# Generated deterministically by seda-macro-lef-normalizer-v1; recipe orfs-ng45-fakeram-metal3-coupledl2-pg-v1.
VERSION 5.8 ;
BUSBITCHARS "[]" ;
DIVIDERCHAR "/" ;

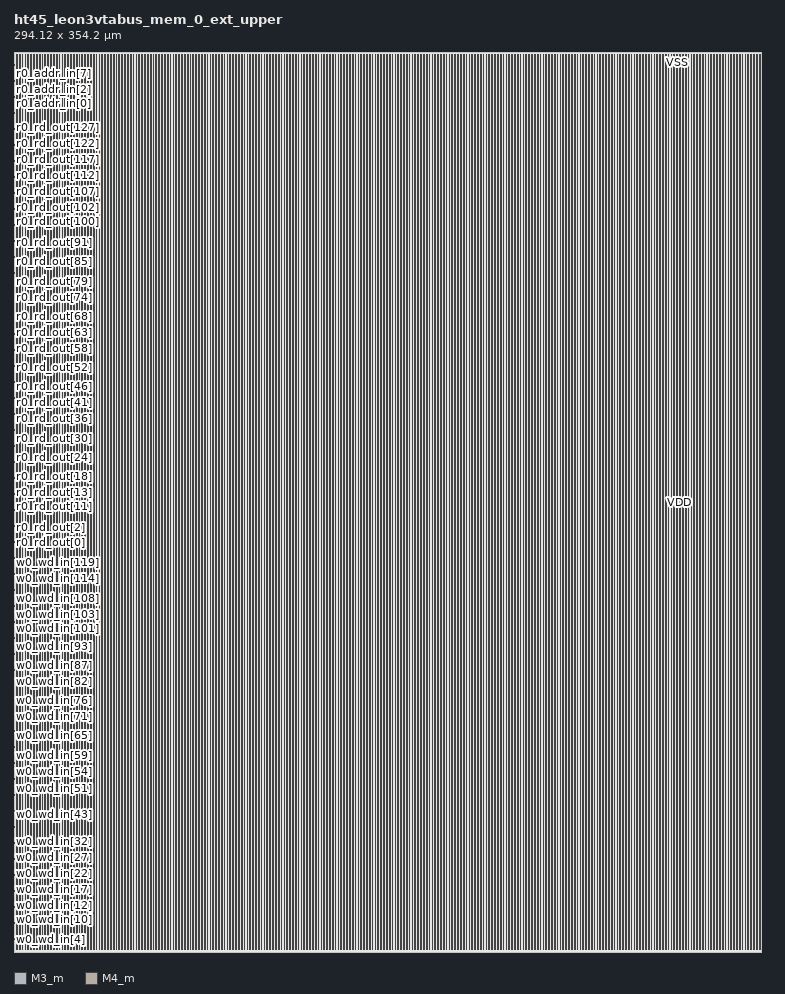
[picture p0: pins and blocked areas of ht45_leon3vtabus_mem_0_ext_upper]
MACRO ht45_leon3vtabus_mem_0_ext_upper
  FOREIGN ht45_leon3vtabus_mem_0_ext_upper 0 0 ;
  CLASS COVER ;
  ORIGIN 0 0 ;
  SIZE 294.12 BY 354.2 ;
  SYMMETRY X Y R90 ;
  PIN w0_wd_in[0]
    DIRECTION INPUT ;
    USE SIGNAL ;
    SHAPE ABUTMENT ;
    PORT
      LAYER M3_m ;
      RECT 0 0.035 0.07 0.105 ;
    END
  END w0_wd_in[0]
  PIN w0_wd_in[1]
    DIRECTION INPUT ;
    USE SIGNAL ;
    SHAPE ABUTMENT ;
    PORT
      LAYER M3_m ;
      RECT 0 1.295 0.07 1.365 ;
    END
  END w0_wd_in[1]
  PIN w0_wd_in[2]
    DIRECTION INPUT ;
    USE SIGNAL ;
    SHAPE ABUTMENT ;
    PORT
      LAYER M3_m ;
      RECT 0 2.555 0.07 2.625 ;
    END
  END w0_wd_in[2]
  PIN w0_wd_in[3]
    DIRECTION INPUT ;
    USE SIGNAL ;
    SHAPE ABUTMENT ;
    PORT
      LAYER M3_m ;
      RECT 0 3.815 0.07 3.885 ;
    END
  END w0_wd_in[3]
  PIN w0_wd_in[4]
    DIRECTION INPUT ;
    USE SIGNAL ;
    SHAPE ABUTMENT ;
    PORT
      LAYER M3_m ;
      RECT 0 5.075 0.07 5.145 ;
    END
  END w0_wd_in[4]
  PIN w0_wd_in[5]
    DIRECTION INPUT ;
    USE SIGNAL ;
    SHAPE ABUTMENT ;
    PORT
      LAYER M3_m ;
      RECT 0 6.335 0.07 6.405 ;
    END
  END w0_wd_in[5]
  PIN w0_wd_in[6]
    DIRECTION INPUT ;
    USE SIGNAL ;
    SHAPE ABUTMENT ;
    PORT
      LAYER M3_m ;
      RECT 0 7.595 0.07 7.665 ;
    END
  END w0_wd_in[6]
  PIN w0_wd_in[7]
    DIRECTION INPUT ;
    USE SIGNAL ;
    SHAPE ABUTMENT ;
    PORT
      LAYER M3_m ;
      RECT 0 8.855 0.07 8.925 ;
    END
  END w0_wd_in[7]
  PIN w0_wd_in[8]
    DIRECTION INPUT ;
    USE SIGNAL ;
    SHAPE ABUTMENT ;
    PORT
      LAYER M3_m ;
      RECT 0 10.115 0.07 10.185 ;
    END
  END w0_wd_in[8]
  PIN w0_wd_in[9]
    DIRECTION INPUT ;
    USE SIGNAL ;
    SHAPE ABUTMENT ;
    PORT
      LAYER M3_m ;
      RECT 0 11.375 0.07 11.445 ;
    END
  END w0_wd_in[9]
  PIN w0_wd_in[10]
    DIRECTION INPUT ;
    USE SIGNAL ;
    SHAPE ABUTMENT ;
    PORT
      LAYER M3_m ;
      RECT 0 12.635 0.07 12.705 ;
    END
  END w0_wd_in[10]
  PIN w0_wd_in[11]
    DIRECTION INPUT ;
    USE SIGNAL ;
    SHAPE ABUTMENT ;
    PORT
      LAYER M3_m ;
      RECT 0 13.895 0.07 13.965 ;
    END
  END w0_wd_in[11]
  PIN w0_wd_in[12]
    DIRECTION INPUT ;
    USE SIGNAL ;
    SHAPE ABUTMENT ;
    PORT
      LAYER M3_m ;
      RECT 0 15.155 0.07 15.225 ;
    END
  END w0_wd_in[12]
  PIN w0_wd_in[13]
    DIRECTION INPUT ;
    USE SIGNAL ;
    SHAPE ABUTMENT ;
    PORT
      LAYER M3_m ;
      RECT 0 16.415 0.07 16.485 ;
    END
  END w0_wd_in[13]
  PIN w0_wd_in[14]
    DIRECTION INPUT ;
    USE SIGNAL ;
    SHAPE ABUTMENT ;
    PORT
      LAYER M3_m ;
      RECT 0 17.675 0.07 17.745 ;
    END
  END w0_wd_in[14]
  PIN w0_wd_in[15]
    DIRECTION INPUT ;
    USE SIGNAL ;
    SHAPE ABUTMENT ;
    PORT
      LAYER M3_m ;
      RECT 0 18.935 0.07 19.005 ;
    END
  END w0_wd_in[15]
  PIN w0_wd_in[16]
    DIRECTION INPUT ;
    USE SIGNAL ;
    SHAPE ABUTMENT ;
    PORT
      LAYER M3_m ;
      RECT 0 20.195 0.07 20.265 ;
    END
  END w0_wd_in[16]
  PIN w0_wd_in[17]
    DIRECTION INPUT ;
    USE SIGNAL ;
    SHAPE ABUTMENT ;
    PORT
      LAYER M3_m ;
      RECT 0 21.455 0.07 21.525 ;
    END
  END w0_wd_in[17]
  PIN w0_wd_in[18]
    DIRECTION INPUT ;
    USE SIGNAL ;
    SHAPE ABUTMENT ;
    PORT
      LAYER M3_m ;
      RECT 0 22.715 0.07 22.785 ;
    END
  END w0_wd_in[18]
  PIN w0_wd_in[19]
    DIRECTION INPUT ;
    USE SIGNAL ;
    SHAPE ABUTMENT ;
    PORT
      LAYER M3_m ;
      RECT 0 23.975 0.07 24.045 ;
    END
  END w0_wd_in[19]
  PIN w0_wd_in[20]
    DIRECTION INPUT ;
    USE SIGNAL ;
    SHAPE ABUTMENT ;
    PORT
      LAYER M3_m ;
      RECT 0 25.235 0.07 25.305 ;
    END
  END w0_wd_in[20]
  PIN w0_wd_in[21]
    DIRECTION INPUT ;
    USE SIGNAL ;
    SHAPE ABUTMENT ;
    PORT
      LAYER M3_m ;
      RECT 0 26.495 0.07 26.565 ;
    END
  END w0_wd_in[21]
  PIN w0_wd_in[22]
    DIRECTION INPUT ;
    USE SIGNAL ;
    SHAPE ABUTMENT ;
    PORT
      LAYER M3_m ;
      RECT 0 27.755 0.07 27.825 ;
    END
  END w0_wd_in[22]
  PIN w0_wd_in[23]
    DIRECTION INPUT ;
    USE SIGNAL ;
    SHAPE ABUTMENT ;
    PORT
      LAYER M3_m ;
      RECT 0 29.015 0.07 29.085 ;
    END
  END w0_wd_in[23]
  PIN w0_wd_in[24]
    DIRECTION INPUT ;
    USE SIGNAL ;
    SHAPE ABUTMENT ;
    PORT
      LAYER M3_m ;
      RECT 0 30.275 0.07 30.345 ;
    END
  END w0_wd_in[24]
  PIN w0_wd_in[25]
    DIRECTION INPUT ;
    USE SIGNAL ;
    SHAPE ABUTMENT ;
    PORT
      LAYER M3_m ;
      RECT 0 31.535 0.07 31.605 ;
    END
  END w0_wd_in[25]
  PIN w0_wd_in[26]
    DIRECTION INPUT ;
    USE SIGNAL ;
    SHAPE ABUTMENT ;
    PORT
      LAYER M3_m ;
      RECT 0 32.795 0.07 32.865 ;
    END
  END w0_wd_in[26]
  PIN w0_wd_in[27]
    DIRECTION INPUT ;
    USE SIGNAL ;
    SHAPE ABUTMENT ;
    PORT
      LAYER M3_m ;
      RECT 0 34.055 0.07 34.125 ;
    END
  END w0_wd_in[27]
  PIN w0_wd_in[28]
    DIRECTION INPUT ;
    USE SIGNAL ;
    SHAPE ABUTMENT ;
    PORT
      LAYER M3_m ;
      RECT 0 35.315 0.07 35.385 ;
    END
  END w0_wd_in[28]
  PIN w0_wd_in[29]
    DIRECTION INPUT ;
    USE SIGNAL ;
    SHAPE ABUTMENT ;
    PORT
      LAYER M3_m ;
      RECT 0 36.575 0.07 36.645 ;
    END
  END w0_wd_in[29]
  PIN w0_wd_in[30]
    DIRECTION INPUT ;
    USE SIGNAL ;
    SHAPE ABUTMENT ;
    PORT
      LAYER M3_m ;
      RECT 0 37.835 0.07 37.905 ;
    END
  END w0_wd_in[30]
  PIN w0_wd_in[31]
    DIRECTION INPUT ;
    USE SIGNAL ;
    SHAPE ABUTMENT ;
    PORT
      LAYER M3_m ;
      RECT 0 39.095 0.07 39.165 ;
    END
  END w0_wd_in[31]
  PIN w0_wd_in[32]
    DIRECTION INPUT ;
    USE SIGNAL ;
    SHAPE ABUTMENT ;
    PORT
      LAYER M3_m ;
      RECT 0 40.355 0.07 40.425 ;
    END
  END w0_wd_in[32]
  PIN w0_wd_in[33]
    DIRECTION INPUT ;
    USE SIGNAL ;
    SHAPE ABUTMENT ;
    PORT
      LAYER M3_m ;
      RECT 0 41.615 0.07 41.685 ;
    END
  END w0_wd_in[33]
  PIN w0_wd_in[34]
    DIRECTION INPUT ;
    USE SIGNAL ;
    SHAPE ABUTMENT ;
    PORT
      LAYER M3_m ;
      RECT 0 42.875 0.07 42.945 ;
    END
  END w0_wd_in[34]
  PIN w0_wd_in[35]
    DIRECTION INPUT ;
    USE SIGNAL ;
    SHAPE ABUTMENT ;
    PORT
      LAYER M3_m ;
      RECT 0 44.135 0.07 44.205 ;
    END
  END w0_wd_in[35]
  PIN w0_wd_in[36]
    DIRECTION INPUT ;
    USE SIGNAL ;
    SHAPE ABUTMENT ;
    PORT
      LAYER M3_m ;
      RECT 0 45.395 0.07 45.465 ;
    END
  END w0_wd_in[36]
  PIN w0_wd_in[37]
    DIRECTION INPUT ;
    USE SIGNAL ;
    SHAPE ABUTMENT ;
    PORT
      LAYER M3_m ;
      RECT 0 46.655 0.07 46.725 ;
    END
  END w0_wd_in[37]
  PIN w0_wd_in[38]
    DIRECTION INPUT ;
    USE SIGNAL ;
    SHAPE ABUTMENT ;
    PORT
      LAYER M3_m ;
      RECT 0 47.915 0.07 47.985 ;
    END
  END w0_wd_in[38]
  PIN w0_wd_in[39]
    DIRECTION INPUT ;
    USE SIGNAL ;
    SHAPE ABUTMENT ;
    PORT
      LAYER M3_m ;
      RECT 0 49.175 0.07 49.245 ;
    END
  END w0_wd_in[39]
  PIN w0_wd_in[40]
    DIRECTION INPUT ;
    USE SIGNAL ;
    SHAPE ABUTMENT ;
    PORT
      LAYER M3_m ;
      RECT 0 50.435 0.07 50.505 ;
    END
  END w0_wd_in[40]
  PIN w0_wd_in[41]
    DIRECTION INPUT ;
    USE SIGNAL ;
    SHAPE ABUTMENT ;
    PORT
      LAYER M3_m ;
      RECT 0 51.695 0.07 51.765 ;
    END
  END w0_wd_in[41]
  PIN w0_wd_in[42]
    DIRECTION INPUT ;
    USE SIGNAL ;
    SHAPE ABUTMENT ;
    PORT
      LAYER M3_m ;
      RECT 0 52.955 0.07 53.025 ;
    END
  END w0_wd_in[42]
  PIN w0_wd_in[43]
    DIRECTION INPUT ;
    USE SIGNAL ;
    SHAPE ABUTMENT ;
    PORT
      LAYER M3_m ;
      RECT 0 54.215 0.07 54.285 ;
    END
  END w0_wd_in[43]
  PIN w0_wd_in[44]
    DIRECTION INPUT ;
    USE SIGNAL ;
    SHAPE ABUTMENT ;
    PORT
      LAYER M3_m ;
      RECT 0 55.475 0.07 55.545 ;
    END
  END w0_wd_in[44]
  PIN w0_wd_in[45]
    DIRECTION INPUT ;
    USE SIGNAL ;
    SHAPE ABUTMENT ;
    PORT
      LAYER M3_m ;
      RECT 0 56.735 0.07 56.805 ;
    END
  END w0_wd_in[45]
  PIN w0_wd_in[46]
    DIRECTION INPUT ;
    USE SIGNAL ;
    SHAPE ABUTMENT ;
    PORT
      LAYER M3_m ;
      RECT 0 57.995 0.07 58.065 ;
    END
  END w0_wd_in[46]
  PIN w0_wd_in[47]
    DIRECTION INPUT ;
    USE SIGNAL ;
    SHAPE ABUTMENT ;
    PORT
      LAYER M3_m ;
      RECT 0 59.255 0.07 59.325 ;
    END
  END w0_wd_in[47]
  PIN w0_wd_in[48]
    DIRECTION INPUT ;
    USE SIGNAL ;
    SHAPE ABUTMENT ;
    PORT
      LAYER M3_m ;
      RECT 0 60.515 0.07 60.585 ;
    END
  END w0_wd_in[48]
  PIN w0_wd_in[49]
    DIRECTION INPUT ;
    USE SIGNAL ;
    SHAPE ABUTMENT ;
    PORT
      LAYER M3_m ;
      RECT 0 61.775 0.07 61.845 ;
    END
  END w0_wd_in[49]
  PIN w0_wd_in[50]
    DIRECTION INPUT ;
    USE SIGNAL ;
    SHAPE ABUTMENT ;
    PORT
      LAYER M3_m ;
      RECT 0 63.035 0.07 63.105 ;
    END
  END w0_wd_in[50]
  PIN w0_wd_in[51]
    DIRECTION INPUT ;
    USE SIGNAL ;
    SHAPE ABUTMENT ;
    PORT
      LAYER M3_m ;
      RECT 0 64.295 0.07 64.365 ;
    END
  END w0_wd_in[51]
  PIN w0_wd_in[52]
    DIRECTION INPUT ;
    USE SIGNAL ;
    SHAPE ABUTMENT ;
    PORT
      LAYER M3_m ;
      RECT 0 65.555 0.07 65.625 ;
    END
  END w0_wd_in[52]
  PIN w0_wd_in[53]
    DIRECTION INPUT ;
    USE SIGNAL ;
    SHAPE ABUTMENT ;
    PORT
      LAYER M3_m ;
      RECT 0 66.815 0.07 66.885 ;
    END
  END w0_wd_in[53]
  PIN w0_wd_in[54]
    DIRECTION INPUT ;
    USE SIGNAL ;
    SHAPE ABUTMENT ;
    PORT
      LAYER M3_m ;
      RECT 0 68.075 0.07 68.145 ;
    END
  END w0_wd_in[54]
  PIN w0_wd_in[55]
    DIRECTION INPUT ;
    USE SIGNAL ;
    SHAPE ABUTMENT ;
    PORT
      LAYER M3_m ;
      RECT 0 69.335 0.07 69.405 ;
    END
  END w0_wd_in[55]
  PIN w0_wd_in[56]
    DIRECTION INPUT ;
    USE SIGNAL ;
    SHAPE ABUTMENT ;
    PORT
      LAYER M3_m ;
      RECT 0 70.595 0.07 70.665 ;
    END
  END w0_wd_in[56]
  PIN w0_wd_in[57]
    DIRECTION INPUT ;
    USE SIGNAL ;
    SHAPE ABUTMENT ;
    PORT
      LAYER M3_m ;
      RECT 0 71.855 0.07 71.925 ;
    END
  END w0_wd_in[57]
  PIN w0_wd_in[58]
    DIRECTION INPUT ;
    USE SIGNAL ;
    SHAPE ABUTMENT ;
    PORT
      LAYER M3_m ;
      RECT 0 73.115 0.07 73.185 ;
    END
  END w0_wd_in[58]
  PIN w0_wd_in[59]
    DIRECTION INPUT ;
    USE SIGNAL ;
    SHAPE ABUTMENT ;
    PORT
      LAYER M3_m ;
      RECT 0 74.375 0.07 74.445 ;
    END
  END w0_wd_in[59]
  PIN w0_wd_in[60]
    DIRECTION INPUT ;
    USE SIGNAL ;
    SHAPE ABUTMENT ;
    PORT
      LAYER M3_m ;
      RECT 0 75.635 0.07 75.705 ;
    END
  END w0_wd_in[60]
  PIN w0_wd_in[61]
    DIRECTION INPUT ;
    USE SIGNAL ;
    SHAPE ABUTMENT ;
    PORT
      LAYER M3_m ;
      RECT 0 76.895 0.07 76.965 ;
    END
  END w0_wd_in[61]
  PIN w0_wd_in[62]
    DIRECTION INPUT ;
    USE SIGNAL ;
    SHAPE ABUTMENT ;
    PORT
      LAYER M3_m ;
      RECT 0 78.155 0.07 78.225 ;
    END
  END w0_wd_in[62]
  PIN w0_wd_in[63]
    DIRECTION INPUT ;
    USE SIGNAL ;
    SHAPE ABUTMENT ;
    PORT
      LAYER M3_m ;
      RECT 0 79.415 0.07 79.485 ;
    END
  END w0_wd_in[63]
  PIN w0_wd_in[64]
    DIRECTION INPUT ;
    USE SIGNAL ;
    SHAPE ABUTMENT ;
    PORT
      LAYER M3_m ;
      RECT 0 80.675 0.07 80.745 ;
    END
  END w0_wd_in[64]
  PIN w0_wd_in[65]
    DIRECTION INPUT ;
    USE SIGNAL ;
    SHAPE ABUTMENT ;
    PORT
      LAYER M3_m ;
      RECT 0 81.935 0.07 82.005 ;
    END
  END w0_wd_in[65]
  PIN w0_wd_in[66]
    DIRECTION INPUT ;
    USE SIGNAL ;
    SHAPE ABUTMENT ;
    PORT
      LAYER M3_m ;
      RECT 0 83.195 0.07 83.265 ;
    END
  END w0_wd_in[66]
  PIN w0_wd_in[67]
    DIRECTION INPUT ;
    USE SIGNAL ;
    SHAPE ABUTMENT ;
    PORT
      LAYER M3_m ;
      RECT 0 84.455 0.07 84.525 ;
    END
  END w0_wd_in[67]
  PIN w0_wd_in[68]
    DIRECTION INPUT ;
    USE SIGNAL ;
    SHAPE ABUTMENT ;
    PORT
      LAYER M3_m ;
      RECT 0 85.715 0.07 85.785 ;
    END
  END w0_wd_in[68]
  PIN w0_wd_in[69]
    DIRECTION INPUT ;
    USE SIGNAL ;
    SHAPE ABUTMENT ;
    PORT
      LAYER M3_m ;
      RECT 0 86.975 0.07 87.045 ;
    END
  END w0_wd_in[69]
  PIN w0_wd_in[70]
    DIRECTION INPUT ;
    USE SIGNAL ;
    SHAPE ABUTMENT ;
    PORT
      LAYER M3_m ;
      RECT 0 88.235 0.07 88.305 ;
    END
  END w0_wd_in[70]
  PIN w0_wd_in[71]
    DIRECTION INPUT ;
    USE SIGNAL ;
    SHAPE ABUTMENT ;
    PORT
      LAYER M3_m ;
      RECT 0 89.495 0.07 89.565 ;
    END
  END w0_wd_in[71]
  PIN w0_wd_in[72]
    DIRECTION INPUT ;
    USE SIGNAL ;
    SHAPE ABUTMENT ;
    PORT
      LAYER M3_m ;
      RECT 0 90.755 0.07 90.825 ;
    END
  END w0_wd_in[72]
  PIN w0_wd_in[73]
    DIRECTION INPUT ;
    USE SIGNAL ;
    SHAPE ABUTMENT ;
    PORT
      LAYER M3_m ;
      RECT 0 92.015 0.07 92.085 ;
    END
  END w0_wd_in[73]
  PIN w0_wd_in[74]
    DIRECTION INPUT ;
    USE SIGNAL ;
    SHAPE ABUTMENT ;
    PORT
      LAYER M3_m ;
      RECT 0 93.275 0.07 93.345 ;
    END
  END w0_wd_in[74]
  PIN w0_wd_in[75]
    DIRECTION INPUT ;
    USE SIGNAL ;
    SHAPE ABUTMENT ;
    PORT
      LAYER M3_m ;
      RECT 0 94.535 0.07 94.605 ;
    END
  END w0_wd_in[75]
  PIN w0_wd_in[76]
    DIRECTION INPUT ;
    USE SIGNAL ;
    SHAPE ABUTMENT ;
    PORT
      LAYER M3_m ;
      RECT 0 95.795 0.07 95.865 ;
    END
  END w0_wd_in[76]
  PIN w0_wd_in[77]
    DIRECTION INPUT ;
    USE SIGNAL ;
    SHAPE ABUTMENT ;
    PORT
      LAYER M3_m ;
      RECT 0 97.055 0.07 97.125 ;
    END
  END w0_wd_in[77]
  PIN w0_wd_in[78]
    DIRECTION INPUT ;
    USE SIGNAL ;
    SHAPE ABUTMENT ;
    PORT
      LAYER M3_m ;
      RECT 0 98.315 0.07 98.385 ;
    END
  END w0_wd_in[78]
  PIN w0_wd_in[79]
    DIRECTION INPUT ;
    USE SIGNAL ;
    SHAPE ABUTMENT ;
    PORT
      LAYER M3_m ;
      RECT 0 99.575 0.07 99.645 ;
    END
  END w0_wd_in[79]
  PIN w0_wd_in[80]
    DIRECTION INPUT ;
    USE SIGNAL ;
    SHAPE ABUTMENT ;
    PORT
      LAYER M3_m ;
      RECT 0 100.835 0.07 100.905 ;
    END
  END w0_wd_in[80]
  PIN w0_wd_in[81]
    DIRECTION INPUT ;
    USE SIGNAL ;
    SHAPE ABUTMENT ;
    PORT
      LAYER M3_m ;
      RECT 0 102.095 0.07 102.165 ;
    END
  END w0_wd_in[81]
  PIN w0_wd_in[82]
    DIRECTION INPUT ;
    USE SIGNAL ;
    SHAPE ABUTMENT ;
    PORT
      LAYER M3_m ;
      RECT 0 103.355 0.07 103.425 ;
    END
  END w0_wd_in[82]
  PIN w0_wd_in[83]
    DIRECTION INPUT ;
    USE SIGNAL ;
    SHAPE ABUTMENT ;
    PORT
      LAYER M3_m ;
      RECT 0 104.615 0.07 104.685 ;
    END
  END w0_wd_in[83]
  PIN w0_wd_in[84]
    DIRECTION INPUT ;
    USE SIGNAL ;
    SHAPE ABUTMENT ;
    PORT
      LAYER M3_m ;
      RECT 0 105.875 0.07 105.945 ;
    END
  END w0_wd_in[84]
  PIN w0_wd_in[85]
    DIRECTION INPUT ;
    USE SIGNAL ;
    SHAPE ABUTMENT ;
    PORT
      LAYER M3_m ;
      RECT 0 107.135 0.07 107.205 ;
    END
  END w0_wd_in[85]
  PIN w0_wd_in[86]
    DIRECTION INPUT ;
    USE SIGNAL ;
    SHAPE ABUTMENT ;
    PORT
      LAYER M3_m ;
      RECT 0 108.395 0.07 108.465 ;
    END
  END w0_wd_in[86]
  PIN w0_wd_in[87]
    DIRECTION INPUT ;
    USE SIGNAL ;
    SHAPE ABUTMENT ;
    PORT
      LAYER M3_m ;
      RECT 0 109.655 0.07 109.725 ;
    END
  END w0_wd_in[87]
  PIN w0_wd_in[88]
    DIRECTION INPUT ;
    USE SIGNAL ;
    SHAPE ABUTMENT ;
    PORT
      LAYER M3_m ;
      RECT 0 110.915 0.07 110.985 ;
    END
  END w0_wd_in[88]
  PIN w0_wd_in[89]
    DIRECTION INPUT ;
    USE SIGNAL ;
    SHAPE ABUTMENT ;
    PORT
      LAYER M3_m ;
      RECT 0 112.175 0.07 112.245 ;
    END
  END w0_wd_in[89]
  PIN w0_wd_in[90]
    DIRECTION INPUT ;
    USE SIGNAL ;
    SHAPE ABUTMENT ;
    PORT
      LAYER M3_m ;
      RECT 0 113.435 0.07 113.505 ;
    END
  END w0_wd_in[90]
  PIN w0_wd_in[91]
    DIRECTION INPUT ;
    USE SIGNAL ;
    SHAPE ABUTMENT ;
    PORT
      LAYER M3_m ;
      RECT 0 114.695 0.07 114.765 ;
    END
  END w0_wd_in[91]
  PIN w0_wd_in[92]
    DIRECTION INPUT ;
    USE SIGNAL ;
    SHAPE ABUTMENT ;
    PORT
      LAYER M3_m ;
      RECT 0 115.955 0.07 116.025 ;
    END
  END w0_wd_in[92]
  PIN w0_wd_in[93]
    DIRECTION INPUT ;
    USE SIGNAL ;
    SHAPE ABUTMENT ;
    PORT
      LAYER M3_m ;
      RECT 0 117.215 0.07 117.285 ;
    END
  END w0_wd_in[93]
  PIN w0_wd_in[94]
    DIRECTION INPUT ;
    USE SIGNAL ;
    SHAPE ABUTMENT ;
    PORT
      LAYER M3_m ;
      RECT 0 118.475 0.07 118.545 ;
    END
  END w0_wd_in[94]
  PIN w0_wd_in[95]
    DIRECTION INPUT ;
    USE SIGNAL ;
    SHAPE ABUTMENT ;
    PORT
      LAYER M3_m ;
      RECT 0 119.735 0.07 119.805 ;
    END
  END w0_wd_in[95]
  PIN w0_wd_in[96]
    DIRECTION INPUT ;
    USE SIGNAL ;
    SHAPE ABUTMENT ;
    PORT
      LAYER M3_m ;
      RECT 0 120.995 0.07 121.065 ;
    END
  END w0_wd_in[96]
  PIN w0_wd_in[97]
    DIRECTION INPUT ;
    USE SIGNAL ;
    SHAPE ABUTMENT ;
    PORT
      LAYER M3_m ;
      RECT 0 122.255 0.07 122.325 ;
    END
  END w0_wd_in[97]
  PIN w0_wd_in[98]
    DIRECTION INPUT ;
    USE SIGNAL ;
    SHAPE ABUTMENT ;
    PORT
      LAYER M3_m ;
      RECT 0 123.515 0.07 123.585 ;
    END
  END w0_wd_in[98]
  PIN w0_wd_in[99]
    DIRECTION INPUT ;
    USE SIGNAL ;
    SHAPE ABUTMENT ;
    PORT
      LAYER M3_m ;
      RECT 0 124.775 0.07 124.845 ;
    END
  END w0_wd_in[99]
  PIN w0_wd_in[100]
    DIRECTION INPUT ;
    USE SIGNAL ;
    SHAPE ABUTMENT ;
    PORT
      LAYER M3_m ;
      RECT 0 126.035 0.07 126.105 ;
    END
  END w0_wd_in[100]
  PIN w0_wd_in[101]
    DIRECTION INPUT ;
    USE SIGNAL ;
    SHAPE ABUTMENT ;
    PORT
      LAYER M3_m ;
      RECT 0 127.295 0.07 127.365 ;
    END
  END w0_wd_in[101]
  PIN w0_wd_in[102]
    DIRECTION INPUT ;
    USE SIGNAL ;
    SHAPE ABUTMENT ;
    PORT
      LAYER M3_m ;
      RECT 0 128.555 0.07 128.625 ;
    END
  END w0_wd_in[102]
  PIN w0_wd_in[103]
    DIRECTION INPUT ;
    USE SIGNAL ;
    SHAPE ABUTMENT ;
    PORT
      LAYER M3_m ;
      RECT 0 129.815 0.07 129.885 ;
    END
  END w0_wd_in[103]
  PIN w0_wd_in[104]
    DIRECTION INPUT ;
    USE SIGNAL ;
    SHAPE ABUTMENT ;
    PORT
      LAYER M3_m ;
      RECT 0 131.075 0.07 131.145 ;
    END
  END w0_wd_in[104]
  PIN w0_wd_in[105]
    DIRECTION INPUT ;
    USE SIGNAL ;
    SHAPE ABUTMENT ;
    PORT
      LAYER M3_m ;
      RECT 0 132.335 0.07 132.405 ;
    END
  END w0_wd_in[105]
  PIN w0_wd_in[106]
    DIRECTION INPUT ;
    USE SIGNAL ;
    SHAPE ABUTMENT ;
    PORT
      LAYER M3_m ;
      RECT 0 133.595 0.07 133.665 ;
    END
  END w0_wd_in[106]
  PIN w0_wd_in[107]
    DIRECTION INPUT ;
    USE SIGNAL ;
    SHAPE ABUTMENT ;
    PORT
      LAYER M3_m ;
      RECT 0 134.855 0.07 134.925 ;
    END
  END w0_wd_in[107]
  PIN w0_wd_in[108]
    DIRECTION INPUT ;
    USE SIGNAL ;
    SHAPE ABUTMENT ;
    PORT
      LAYER M3_m ;
      RECT 0 136.115 0.07 136.185 ;
    END
  END w0_wd_in[108]
  PIN w0_wd_in[109]
    DIRECTION INPUT ;
    USE SIGNAL ;
    SHAPE ABUTMENT ;
    PORT
      LAYER M3_m ;
      RECT 0 137.375 0.07 137.445 ;
    END
  END w0_wd_in[109]
  PIN w0_wd_in[110]
    DIRECTION INPUT ;
    USE SIGNAL ;
    SHAPE ABUTMENT ;
    PORT
      LAYER M3_m ;
      RECT 0 138.635 0.07 138.705 ;
    END
  END w0_wd_in[110]
  PIN w0_wd_in[111]
    DIRECTION INPUT ;
    USE SIGNAL ;
    SHAPE ABUTMENT ;
    PORT
      LAYER M3_m ;
      RECT 0 139.895 0.07 139.965 ;
    END
  END w0_wd_in[111]
  PIN w0_wd_in[112]
    DIRECTION INPUT ;
    USE SIGNAL ;
    SHAPE ABUTMENT ;
    PORT
      LAYER M3_m ;
      RECT 0 141.155 0.07 141.225 ;
    END
  END w0_wd_in[112]
  PIN w0_wd_in[113]
    DIRECTION INPUT ;
    USE SIGNAL ;
    SHAPE ABUTMENT ;
    PORT
      LAYER M3_m ;
      RECT 0 142.415 0.07 142.485 ;
    END
  END w0_wd_in[113]
  PIN w0_wd_in[114]
    DIRECTION INPUT ;
    USE SIGNAL ;
    SHAPE ABUTMENT ;
    PORT
      LAYER M3_m ;
      RECT 0 143.675 0.07 143.745 ;
    END
  END w0_wd_in[114]
  PIN w0_wd_in[115]
    DIRECTION INPUT ;
    USE SIGNAL ;
    SHAPE ABUTMENT ;
    PORT
      LAYER M3_m ;
      RECT 0 144.935 0.07 145.005 ;
    END
  END w0_wd_in[115]
  PIN w0_wd_in[116]
    DIRECTION INPUT ;
    USE SIGNAL ;
    SHAPE ABUTMENT ;
    PORT
      LAYER M3_m ;
      RECT 0 146.195 0.07 146.265 ;
    END
  END w0_wd_in[116]
  PIN w0_wd_in[117]
    DIRECTION INPUT ;
    USE SIGNAL ;
    SHAPE ABUTMENT ;
    PORT
      LAYER M3_m ;
      RECT 0 147.455 0.07 147.525 ;
    END
  END w0_wd_in[117]
  PIN w0_wd_in[118]
    DIRECTION INPUT ;
    USE SIGNAL ;
    SHAPE ABUTMENT ;
    PORT
      LAYER M3_m ;
      RECT 0 148.715 0.07 148.785 ;
    END
  END w0_wd_in[118]
  PIN w0_wd_in[119]
    DIRECTION INPUT ;
    USE SIGNAL ;
    SHAPE ABUTMENT ;
    PORT
      LAYER M3_m ;
      RECT 0 149.975 0.07 150.045 ;
    END
  END w0_wd_in[119]
  PIN w0_wd_in[120]
    DIRECTION INPUT ;
    USE SIGNAL ;
    SHAPE ABUTMENT ;
    PORT
      LAYER M3_m ;
      RECT 0 151.235 0.07 151.305 ;
    END
  END w0_wd_in[120]
  PIN w0_wd_in[121]
    DIRECTION INPUT ;
    USE SIGNAL ;
    SHAPE ABUTMENT ;
    PORT
      LAYER M3_m ;
      RECT 0 152.495 0.07 152.565 ;
    END
  END w0_wd_in[121]
  PIN w0_wd_in[122]
    DIRECTION INPUT ;
    USE SIGNAL ;
    SHAPE ABUTMENT ;
    PORT
      LAYER M3_m ;
      RECT 0 153.755 0.07 153.825 ;
    END
  END w0_wd_in[122]
  PIN w0_wd_in[123]
    DIRECTION INPUT ;
    USE SIGNAL ;
    SHAPE ABUTMENT ;
    PORT
      LAYER M3_m ;
      RECT 0 155.015 0.07 155.085 ;
    END
  END w0_wd_in[123]
  PIN w0_wd_in[124]
    DIRECTION INPUT ;
    USE SIGNAL ;
    SHAPE ABUTMENT ;
    PORT
      LAYER M3_m ;
      RECT 0 156.275 0.07 156.345 ;
    END
  END w0_wd_in[124]
  PIN w0_wd_in[125]
    DIRECTION INPUT ;
    USE SIGNAL ;
    SHAPE ABUTMENT ;
    PORT
      LAYER M3_m ;
      RECT 0 157.535 0.07 157.605 ;
    END
  END w0_wd_in[125]
  PIN w0_wd_in[126]
    DIRECTION INPUT ;
    USE SIGNAL ;
    SHAPE ABUTMENT ;
    PORT
      LAYER M3_m ;
      RECT 0 158.795 0.07 158.865 ;
    END
  END w0_wd_in[126]
  PIN w0_wd_in[127]
    DIRECTION INPUT ;
    USE SIGNAL ;
    SHAPE ABUTMENT ;
    PORT
      LAYER M3_m ;
      RECT 0 160.055 0.07 160.125 ;
    END
  END w0_wd_in[127]
  PIN r0_rd_out[0]
    DIRECTION OUTPUT ;
    USE SIGNAL ;
    SHAPE ABUTMENT ;
    PORT
      LAYER M3_m ;
      RECT 0 161.315 0.07 161.385 ;
    END
  END r0_rd_out[0]
  PIN r0_rd_out[1]
    DIRECTION OUTPUT ;
    USE SIGNAL ;
    SHAPE ABUTMENT ;
    PORT
      LAYER M3_m ;
      RECT 0 162.575 0.07 162.645 ;
    END
  END r0_rd_out[1]
  PIN r0_rd_out[2]
    DIRECTION OUTPUT ;
    USE SIGNAL ;
    SHAPE ABUTMENT ;
    PORT
      LAYER M3_m ;
      RECT 0 163.835 0.07 163.905 ;
    END
  END r0_rd_out[2]
  PIN r0_rd_out[3]
    DIRECTION OUTPUT ;
    USE SIGNAL ;
    SHAPE ABUTMENT ;
    PORT
      LAYER M3_m ;
      RECT 0 165.095 0.07 165.165 ;
    END
  END r0_rd_out[3]
  PIN r0_rd_out[4]
    DIRECTION OUTPUT ;
    USE SIGNAL ;
    SHAPE ABUTMENT ;
    PORT
      LAYER M3_m ;
      RECT 0 166.355 0.07 166.425 ;
    END
  END r0_rd_out[4]
  PIN r0_rd_out[5]
    DIRECTION OUTPUT ;
    USE SIGNAL ;
    SHAPE ABUTMENT ;
    PORT
      LAYER M3_m ;
      RECT 0 167.615 0.07 167.685 ;
    END
  END r0_rd_out[5]
  PIN r0_rd_out[6]
    DIRECTION OUTPUT ;
    USE SIGNAL ;
    SHAPE ABUTMENT ;
    PORT
      LAYER M3_m ;
      RECT 0 168.875 0.07 168.945 ;
    END
  END r0_rd_out[6]
  PIN r0_rd_out[7]
    DIRECTION OUTPUT ;
    USE SIGNAL ;
    SHAPE ABUTMENT ;
    PORT
      LAYER M3_m ;
      RECT 0 170.135 0.07 170.205 ;
    END
  END r0_rd_out[7]
  PIN r0_rd_out[8]
    DIRECTION OUTPUT ;
    USE SIGNAL ;
    SHAPE ABUTMENT ;
    PORT
      LAYER M3_m ;
      RECT 0 171.395 0.07 171.465 ;
    END
  END r0_rd_out[8]
  PIN r0_rd_out[9]
    DIRECTION OUTPUT ;
    USE SIGNAL ;
    SHAPE ABUTMENT ;
    PORT
      LAYER M3_m ;
      RECT 0 172.655 0.07 172.725 ;
    END
  END r0_rd_out[9]
  PIN r0_rd_out[10]
    DIRECTION OUTPUT ;
    USE SIGNAL ;
    SHAPE ABUTMENT ;
    PORT
      LAYER M3_m ;
      RECT 0 173.915 0.07 173.985 ;
    END
  END r0_rd_out[10]
  PIN r0_rd_out[11]
    DIRECTION OUTPUT ;
    USE SIGNAL ;
    SHAPE ABUTMENT ;
    PORT
      LAYER M3_m ;
      RECT 0 175.175 0.07 175.245 ;
    END
  END r0_rd_out[11]
  PIN r0_rd_out[12]
    DIRECTION OUTPUT ;
    USE SIGNAL ;
    SHAPE ABUTMENT ;
    PORT
      LAYER M3_m ;
      RECT 0 176.435 0.07 176.505 ;
    END
  END r0_rd_out[12]
  PIN r0_rd_out[13]
    DIRECTION OUTPUT ;
    USE SIGNAL ;
    SHAPE ABUTMENT ;
    PORT
      LAYER M3_m ;
      RECT 0 177.695 0.07 177.765 ;
    END
  END r0_rd_out[13]
  PIN r0_rd_out[14]
    DIRECTION OUTPUT ;
    USE SIGNAL ;
    SHAPE ABUTMENT ;
    PORT
      LAYER M3_m ;
      RECT 0 178.955 0.07 179.025 ;
    END
  END r0_rd_out[14]
  PIN r0_rd_out[15]
    DIRECTION OUTPUT ;
    USE SIGNAL ;
    SHAPE ABUTMENT ;
    PORT
      LAYER M3_m ;
      RECT 0 180.215 0.07 180.285 ;
    END
  END r0_rd_out[15]
  PIN r0_rd_out[16]
    DIRECTION OUTPUT ;
    USE SIGNAL ;
    SHAPE ABUTMENT ;
    PORT
      LAYER M3_m ;
      RECT 0 181.475 0.07 181.545 ;
    END
  END r0_rd_out[16]
  PIN r0_rd_out[17]
    DIRECTION OUTPUT ;
    USE SIGNAL ;
    SHAPE ABUTMENT ;
    PORT
      LAYER M3_m ;
      RECT 0 182.735 0.07 182.805 ;
    END
  END r0_rd_out[17]
  PIN r0_rd_out[18]
    DIRECTION OUTPUT ;
    USE SIGNAL ;
    SHAPE ABUTMENT ;
    PORT
      LAYER M3_m ;
      RECT 0 183.995 0.07 184.065 ;
    END
  END r0_rd_out[18]
  PIN r0_rd_out[19]
    DIRECTION OUTPUT ;
    USE SIGNAL ;
    SHAPE ABUTMENT ;
    PORT
      LAYER M3_m ;
      RECT 0 185.255 0.07 185.325 ;
    END
  END r0_rd_out[19]
  PIN r0_rd_out[20]
    DIRECTION OUTPUT ;
    USE SIGNAL ;
    SHAPE ABUTMENT ;
    PORT
      LAYER M3_m ;
      RECT 0 186.515 0.07 186.585 ;
    END
  END r0_rd_out[20]
  PIN r0_rd_out[21]
    DIRECTION OUTPUT ;
    USE SIGNAL ;
    SHAPE ABUTMENT ;
    PORT
      LAYER M3_m ;
      RECT 0 187.775 0.07 187.845 ;
    END
  END r0_rd_out[21]
  PIN r0_rd_out[22]
    DIRECTION OUTPUT ;
    USE SIGNAL ;
    SHAPE ABUTMENT ;
    PORT
      LAYER M3_m ;
      RECT 0 189.035 0.07 189.105 ;
    END
  END r0_rd_out[22]
  PIN r0_rd_out[23]
    DIRECTION OUTPUT ;
    USE SIGNAL ;
    SHAPE ABUTMENT ;
    PORT
      LAYER M3_m ;
      RECT 0 190.295 0.07 190.365 ;
    END
  END r0_rd_out[23]
  PIN r0_rd_out[24]
    DIRECTION OUTPUT ;
    USE SIGNAL ;
    SHAPE ABUTMENT ;
    PORT
      LAYER M3_m ;
      RECT 0 191.555 0.07 191.625 ;
    END
  END r0_rd_out[24]
  PIN r0_rd_out[25]
    DIRECTION OUTPUT ;
    USE SIGNAL ;
    SHAPE ABUTMENT ;
    PORT
      LAYER M3_m ;
      RECT 0 192.815 0.07 192.885 ;
    END
  END r0_rd_out[25]
  PIN r0_rd_out[26]
    DIRECTION OUTPUT ;
    USE SIGNAL ;
    SHAPE ABUTMENT ;
    PORT
      LAYER M3_m ;
      RECT 0 194.075 0.07 194.145 ;
    END
  END r0_rd_out[26]
  PIN r0_rd_out[27]
    DIRECTION OUTPUT ;
    USE SIGNAL ;
    SHAPE ABUTMENT ;
    PORT
      LAYER M3_m ;
      RECT 0 195.335 0.07 195.405 ;
    END
  END r0_rd_out[27]
  PIN r0_rd_out[28]
    DIRECTION OUTPUT ;
    USE SIGNAL ;
    SHAPE ABUTMENT ;
    PORT
      LAYER M3_m ;
      RECT 0 196.595 0.07 196.665 ;
    END
  END r0_rd_out[28]
  PIN r0_rd_out[29]
    DIRECTION OUTPUT ;
    USE SIGNAL ;
    SHAPE ABUTMENT ;
    PORT
      LAYER M3_m ;
      RECT 0 197.855 0.07 197.925 ;
    END
  END r0_rd_out[29]
  PIN r0_rd_out[30]
    DIRECTION OUTPUT ;
    USE SIGNAL ;
    SHAPE ABUTMENT ;
    PORT
      LAYER M3_m ;
      RECT 0 199.115 0.07 199.185 ;
    END
  END r0_rd_out[30]
  PIN r0_rd_out[31]
    DIRECTION OUTPUT ;
    USE SIGNAL ;
    SHAPE ABUTMENT ;
    PORT
      LAYER M3_m ;
      RECT 0 200.375 0.07 200.445 ;
    END
  END r0_rd_out[31]
  PIN r0_rd_out[32]
    DIRECTION OUTPUT ;
    USE SIGNAL ;
    SHAPE ABUTMENT ;
    PORT
      LAYER M3_m ;
      RECT 0 201.635 0.07 201.705 ;
    END
  END r0_rd_out[32]
  PIN r0_rd_out[33]
    DIRECTION OUTPUT ;
    USE SIGNAL ;
    SHAPE ABUTMENT ;
    PORT
      LAYER M3_m ;
      RECT 0 202.895 0.07 202.965 ;
    END
  END r0_rd_out[33]
  PIN r0_rd_out[34]
    DIRECTION OUTPUT ;
    USE SIGNAL ;
    SHAPE ABUTMENT ;
    PORT
      LAYER M3_m ;
      RECT 0 204.155 0.07 204.225 ;
    END
  END r0_rd_out[34]
  PIN r0_rd_out[35]
    DIRECTION OUTPUT ;
    USE SIGNAL ;
    SHAPE ABUTMENT ;
    PORT
      LAYER M3_m ;
      RECT 0 205.415 0.07 205.485 ;
    END
  END r0_rd_out[35]
  PIN r0_rd_out[36]
    DIRECTION OUTPUT ;
    USE SIGNAL ;
    SHAPE ABUTMENT ;
    PORT
      LAYER M3_m ;
      RECT 0 206.675 0.07 206.745 ;
    END
  END r0_rd_out[36]
  PIN r0_rd_out[37]
    DIRECTION OUTPUT ;
    USE SIGNAL ;
    SHAPE ABUTMENT ;
    PORT
      LAYER M3_m ;
      RECT 0 207.935 0.07 208.005 ;
    END
  END r0_rd_out[37]
  PIN r0_rd_out[38]
    DIRECTION OUTPUT ;
    USE SIGNAL ;
    SHAPE ABUTMENT ;
    PORT
      LAYER M3_m ;
      RECT 0 209.195 0.07 209.265 ;
    END
  END r0_rd_out[38]
  PIN r0_rd_out[39]
    DIRECTION OUTPUT ;
    USE SIGNAL ;
    SHAPE ABUTMENT ;
    PORT
      LAYER M3_m ;
      RECT 0 210.455 0.07 210.525 ;
    END
  END r0_rd_out[39]
  PIN r0_rd_out[40]
    DIRECTION OUTPUT ;
    USE SIGNAL ;
    SHAPE ABUTMENT ;
    PORT
      LAYER M3_m ;
      RECT 0 211.715 0.07 211.785 ;
    END
  END r0_rd_out[40]
  PIN r0_rd_out[41]
    DIRECTION OUTPUT ;
    USE SIGNAL ;
    SHAPE ABUTMENT ;
    PORT
      LAYER M3_m ;
      RECT 0 212.975 0.07 213.045 ;
    END
  END r0_rd_out[41]
  PIN r0_rd_out[42]
    DIRECTION OUTPUT ;
    USE SIGNAL ;
    SHAPE ABUTMENT ;
    PORT
      LAYER M3_m ;
      RECT 0 214.235 0.07 214.305 ;
    END
  END r0_rd_out[42]
  PIN r0_rd_out[43]
    DIRECTION OUTPUT ;
    USE SIGNAL ;
    SHAPE ABUTMENT ;
    PORT
      LAYER M3_m ;
      RECT 0 215.495 0.07 215.565 ;
    END
  END r0_rd_out[43]
  PIN r0_rd_out[44]
    DIRECTION OUTPUT ;
    USE SIGNAL ;
    SHAPE ABUTMENT ;
    PORT
      LAYER M3_m ;
      RECT 0 216.755 0.07 216.825 ;
    END
  END r0_rd_out[44]
  PIN r0_rd_out[45]
    DIRECTION OUTPUT ;
    USE SIGNAL ;
    SHAPE ABUTMENT ;
    PORT
      LAYER M3_m ;
      RECT 0 218.015 0.07 218.085 ;
    END
  END r0_rd_out[45]
  PIN r0_rd_out[46]
    DIRECTION OUTPUT ;
    USE SIGNAL ;
    SHAPE ABUTMENT ;
    PORT
      LAYER M3_m ;
      RECT 0 219.275 0.07 219.345 ;
    END
  END r0_rd_out[46]
  PIN r0_rd_out[47]
    DIRECTION OUTPUT ;
    USE SIGNAL ;
    SHAPE ABUTMENT ;
    PORT
      LAYER M3_m ;
      RECT 0 220.535 0.07 220.605 ;
    END
  END r0_rd_out[47]
  PIN r0_rd_out[48]
    DIRECTION OUTPUT ;
    USE SIGNAL ;
    SHAPE ABUTMENT ;
    PORT
      LAYER M3_m ;
      RECT 0 221.795 0.07 221.865 ;
    END
  END r0_rd_out[48]
  PIN r0_rd_out[49]
    DIRECTION OUTPUT ;
    USE SIGNAL ;
    SHAPE ABUTMENT ;
    PORT
      LAYER M3_m ;
      RECT 0 223.055 0.07 223.125 ;
    END
  END r0_rd_out[49]
  PIN r0_rd_out[50]
    DIRECTION OUTPUT ;
    USE SIGNAL ;
    SHAPE ABUTMENT ;
    PORT
      LAYER M3_m ;
      RECT 0 224.315 0.07 224.385 ;
    END
  END r0_rd_out[50]
  PIN r0_rd_out[51]
    DIRECTION OUTPUT ;
    USE SIGNAL ;
    SHAPE ABUTMENT ;
    PORT
      LAYER M3_m ;
      RECT 0 225.575 0.07 225.645 ;
    END
  END r0_rd_out[51]
  PIN r0_rd_out[52]
    DIRECTION OUTPUT ;
    USE SIGNAL ;
    SHAPE ABUTMENT ;
    PORT
      LAYER M3_m ;
      RECT 0 226.835 0.07 226.905 ;
    END
  END r0_rd_out[52]
  PIN r0_rd_out[53]
    DIRECTION OUTPUT ;
    USE SIGNAL ;
    SHAPE ABUTMENT ;
    PORT
      LAYER M3_m ;
      RECT 0 228.095 0.07 228.165 ;
    END
  END r0_rd_out[53]
  PIN r0_rd_out[54]
    DIRECTION OUTPUT ;
    USE SIGNAL ;
    SHAPE ABUTMENT ;
    PORT
      LAYER M3_m ;
      RECT 0 229.355 0.07 229.425 ;
    END
  END r0_rd_out[54]
  PIN r0_rd_out[55]
    DIRECTION OUTPUT ;
    USE SIGNAL ;
    SHAPE ABUTMENT ;
    PORT
      LAYER M3_m ;
      RECT 0 230.615 0.07 230.685 ;
    END
  END r0_rd_out[55]
  PIN r0_rd_out[56]
    DIRECTION OUTPUT ;
    USE SIGNAL ;
    SHAPE ABUTMENT ;
    PORT
      LAYER M3_m ;
      RECT 0 231.875 0.07 231.945 ;
    END
  END r0_rd_out[56]
  PIN r0_rd_out[57]
    DIRECTION OUTPUT ;
    USE SIGNAL ;
    SHAPE ABUTMENT ;
    PORT
      LAYER M3_m ;
      RECT 0 233.135 0.07 233.205 ;
    END
  END r0_rd_out[57]
  PIN r0_rd_out[58]
    DIRECTION OUTPUT ;
    USE SIGNAL ;
    SHAPE ABUTMENT ;
    PORT
      LAYER M3_m ;
      RECT 0 234.395 0.07 234.465 ;
    END
  END r0_rd_out[58]
  PIN r0_rd_out[59]
    DIRECTION OUTPUT ;
    USE SIGNAL ;
    SHAPE ABUTMENT ;
    PORT
      LAYER M3_m ;
      RECT 0 235.655 0.07 235.725 ;
    END
  END r0_rd_out[59]
  PIN r0_rd_out[60]
    DIRECTION OUTPUT ;
    USE SIGNAL ;
    SHAPE ABUTMENT ;
    PORT
      LAYER M3_m ;
      RECT 0 236.915 0.07 236.985 ;
    END
  END r0_rd_out[60]
  PIN r0_rd_out[61]
    DIRECTION OUTPUT ;
    USE SIGNAL ;
    SHAPE ABUTMENT ;
    PORT
      LAYER M3_m ;
      RECT 0 238.175 0.07 238.245 ;
    END
  END r0_rd_out[61]
  PIN r0_rd_out[62]
    DIRECTION OUTPUT ;
    USE SIGNAL ;
    SHAPE ABUTMENT ;
    PORT
      LAYER M3_m ;
      RECT 0 239.435 0.07 239.505 ;
    END
  END r0_rd_out[62]
  PIN r0_rd_out[63]
    DIRECTION OUTPUT ;
    USE SIGNAL ;
    SHAPE ABUTMENT ;
    PORT
      LAYER M3_m ;
      RECT 0 240.695 0.07 240.765 ;
    END
  END r0_rd_out[63]
  PIN r0_rd_out[64]
    DIRECTION OUTPUT ;
    USE SIGNAL ;
    SHAPE ABUTMENT ;
    PORT
      LAYER M3_m ;
      RECT 0 241.955 0.07 242.025 ;
    END
  END r0_rd_out[64]
  PIN r0_rd_out[65]
    DIRECTION OUTPUT ;
    USE SIGNAL ;
    SHAPE ABUTMENT ;
    PORT
      LAYER M3_m ;
      RECT 0 243.215 0.07 243.285 ;
    END
  END r0_rd_out[65]
  PIN r0_rd_out[66]
    DIRECTION OUTPUT ;
    USE SIGNAL ;
    SHAPE ABUTMENT ;
    PORT
      LAYER M3_m ;
      RECT 0 244.475 0.07 244.545 ;
    END
  END r0_rd_out[66]
  PIN r0_rd_out[67]
    DIRECTION OUTPUT ;
    USE SIGNAL ;
    SHAPE ABUTMENT ;
    PORT
      LAYER M3_m ;
      RECT 0 245.735 0.07 245.805 ;
    END
  END r0_rd_out[67]
  PIN r0_rd_out[68]
    DIRECTION OUTPUT ;
    USE SIGNAL ;
    SHAPE ABUTMENT ;
    PORT
      LAYER M3_m ;
      RECT 0 246.995 0.07 247.065 ;
    END
  END r0_rd_out[68]
  PIN r0_rd_out[69]
    DIRECTION OUTPUT ;
    USE SIGNAL ;
    SHAPE ABUTMENT ;
    PORT
      LAYER M3_m ;
      RECT 0 248.255 0.07 248.325 ;
    END
  END r0_rd_out[69]
  PIN r0_rd_out[70]
    DIRECTION OUTPUT ;
    USE SIGNAL ;
    SHAPE ABUTMENT ;
    PORT
      LAYER M3_m ;
      RECT 0 249.515 0.07 249.585 ;
    END
  END r0_rd_out[70]
  PIN r0_rd_out[71]
    DIRECTION OUTPUT ;
    USE SIGNAL ;
    SHAPE ABUTMENT ;
    PORT
      LAYER M3_m ;
      RECT 0 250.775 0.07 250.845 ;
    END
  END r0_rd_out[71]
  PIN r0_rd_out[72]
    DIRECTION OUTPUT ;
    USE SIGNAL ;
    SHAPE ABUTMENT ;
    PORT
      LAYER M3_m ;
      RECT 0 252.035 0.07 252.105 ;
    END
  END r0_rd_out[72]
  PIN r0_rd_out[73]
    DIRECTION OUTPUT ;
    USE SIGNAL ;
    SHAPE ABUTMENT ;
    PORT
      LAYER M3_m ;
      RECT 0 253.295 0.07 253.365 ;
    END
  END r0_rd_out[73]
  PIN r0_rd_out[74]
    DIRECTION OUTPUT ;
    USE SIGNAL ;
    SHAPE ABUTMENT ;
    PORT
      LAYER M3_m ;
      RECT 0 254.555 0.07 254.625 ;
    END
  END r0_rd_out[74]
  PIN r0_rd_out[75]
    DIRECTION OUTPUT ;
    USE SIGNAL ;
    SHAPE ABUTMENT ;
    PORT
      LAYER M3_m ;
      RECT 0 255.815 0.07 255.885 ;
    END
  END r0_rd_out[75]
  PIN r0_rd_out[76]
    DIRECTION OUTPUT ;
    USE SIGNAL ;
    SHAPE ABUTMENT ;
    PORT
      LAYER M3_m ;
      RECT 0 257.075 0.07 257.145 ;
    END
  END r0_rd_out[76]
  PIN r0_rd_out[77]
    DIRECTION OUTPUT ;
    USE SIGNAL ;
    SHAPE ABUTMENT ;
    PORT
      LAYER M3_m ;
      RECT 0 258.335 0.07 258.405 ;
    END
  END r0_rd_out[77]
  PIN r0_rd_out[78]
    DIRECTION OUTPUT ;
    USE SIGNAL ;
    SHAPE ABUTMENT ;
    PORT
      LAYER M3_m ;
      RECT 0 259.595 0.07 259.665 ;
    END
  END r0_rd_out[78]
  PIN r0_rd_out[79]
    DIRECTION OUTPUT ;
    USE SIGNAL ;
    SHAPE ABUTMENT ;
    PORT
      LAYER M3_m ;
      RECT 0 260.855 0.07 260.925 ;
    END
  END r0_rd_out[79]
  PIN r0_rd_out[80]
    DIRECTION OUTPUT ;
    USE SIGNAL ;
    SHAPE ABUTMENT ;
    PORT
      LAYER M3_m ;
      RECT 0 262.115 0.07 262.185 ;
    END
  END r0_rd_out[80]
  PIN r0_rd_out[81]
    DIRECTION OUTPUT ;
    USE SIGNAL ;
    SHAPE ABUTMENT ;
    PORT
      LAYER M3_m ;
      RECT 0 263.375 0.07 263.445 ;
    END
  END r0_rd_out[81]
  PIN r0_rd_out[82]
    DIRECTION OUTPUT ;
    USE SIGNAL ;
    SHAPE ABUTMENT ;
    PORT
      LAYER M3_m ;
      RECT 0 264.635 0.07 264.705 ;
    END
  END r0_rd_out[82]
  PIN r0_rd_out[83]
    DIRECTION OUTPUT ;
    USE SIGNAL ;
    SHAPE ABUTMENT ;
    PORT
      LAYER M3_m ;
      RECT 0 265.895 0.07 265.965 ;
    END
  END r0_rd_out[83]
  PIN r0_rd_out[84]
    DIRECTION OUTPUT ;
    USE SIGNAL ;
    SHAPE ABUTMENT ;
    PORT
      LAYER M3_m ;
      RECT 0 267.155 0.07 267.225 ;
    END
  END r0_rd_out[84]
  PIN r0_rd_out[85]
    DIRECTION OUTPUT ;
    USE SIGNAL ;
    SHAPE ABUTMENT ;
    PORT
      LAYER M3_m ;
      RECT 0 268.415 0.07 268.485 ;
    END
  END r0_rd_out[85]
  PIN r0_rd_out[86]
    DIRECTION OUTPUT ;
    USE SIGNAL ;
    SHAPE ABUTMENT ;
    PORT
      LAYER M3_m ;
      RECT 0 269.675 0.07 269.745 ;
    END
  END r0_rd_out[86]
  PIN r0_rd_out[87]
    DIRECTION OUTPUT ;
    USE SIGNAL ;
    SHAPE ABUTMENT ;
    PORT
      LAYER M3_m ;
      RECT 0 270.935 0.07 271.005 ;
    END
  END r0_rd_out[87]
  PIN r0_rd_out[88]
    DIRECTION OUTPUT ;
    USE SIGNAL ;
    SHAPE ABUTMENT ;
    PORT
      LAYER M3_m ;
      RECT 0 272.195 0.07 272.265 ;
    END
  END r0_rd_out[88]
  PIN r0_rd_out[89]
    DIRECTION OUTPUT ;
    USE SIGNAL ;
    SHAPE ABUTMENT ;
    PORT
      LAYER M3_m ;
      RECT 0 273.455 0.07 273.525 ;
    END
  END r0_rd_out[89]
  PIN r0_rd_out[90]
    DIRECTION OUTPUT ;
    USE SIGNAL ;
    SHAPE ABUTMENT ;
    PORT
      LAYER M3_m ;
      RECT 0 274.715 0.07 274.785 ;
    END
  END r0_rd_out[90]
  PIN r0_rd_out[91]
    DIRECTION OUTPUT ;
    USE SIGNAL ;
    SHAPE ABUTMENT ;
    PORT
      LAYER M3_m ;
      RECT 0 275.975 0.07 276.045 ;
    END
  END r0_rd_out[91]
  PIN r0_rd_out[92]
    DIRECTION OUTPUT ;
    USE SIGNAL ;
    SHAPE ABUTMENT ;
    PORT
      LAYER M3_m ;
      RECT 0 277.235 0.07 277.305 ;
    END
  END r0_rd_out[92]
  PIN r0_rd_out[93]
    DIRECTION OUTPUT ;
    USE SIGNAL ;
    SHAPE ABUTMENT ;
    PORT
      LAYER M3_m ;
      RECT 0 278.495 0.07 278.565 ;
    END
  END r0_rd_out[93]
  PIN r0_rd_out[94]
    DIRECTION OUTPUT ;
    USE SIGNAL ;
    SHAPE ABUTMENT ;
    PORT
      LAYER M3_m ;
      RECT 0 279.755 0.07 279.825 ;
    END
  END r0_rd_out[94]
  PIN r0_rd_out[95]
    DIRECTION OUTPUT ;
    USE SIGNAL ;
    SHAPE ABUTMENT ;
    PORT
      LAYER M3_m ;
      RECT 0 281.015 0.07 281.085 ;
    END
  END r0_rd_out[95]
  PIN r0_rd_out[96]
    DIRECTION OUTPUT ;
    USE SIGNAL ;
    SHAPE ABUTMENT ;
    PORT
      LAYER M3_m ;
      RECT 0 282.275 0.07 282.345 ;
    END
  END r0_rd_out[96]
  PIN r0_rd_out[97]
    DIRECTION OUTPUT ;
    USE SIGNAL ;
    SHAPE ABUTMENT ;
    PORT
      LAYER M3_m ;
      RECT 0 283.535 0.07 283.605 ;
    END
  END r0_rd_out[97]
  PIN r0_rd_out[98]
    DIRECTION OUTPUT ;
    USE SIGNAL ;
    SHAPE ABUTMENT ;
    PORT
      LAYER M3_m ;
      RECT 0 284.795 0.07 284.865 ;
    END
  END r0_rd_out[98]
  PIN r0_rd_out[99]
    DIRECTION OUTPUT ;
    USE SIGNAL ;
    SHAPE ABUTMENT ;
    PORT
      LAYER M3_m ;
      RECT 0 286.055 0.07 286.125 ;
    END
  END r0_rd_out[99]
  PIN r0_rd_out[100]
    DIRECTION OUTPUT ;
    USE SIGNAL ;
    SHAPE ABUTMENT ;
    PORT
      LAYER M3_m ;
      RECT 0 287.315 0.07 287.385 ;
    END
  END r0_rd_out[100]
  PIN r0_rd_out[101]
    DIRECTION OUTPUT ;
    USE SIGNAL ;
    SHAPE ABUTMENT ;
    PORT
      LAYER M3_m ;
      RECT 0 288.575 0.07 288.645 ;
    END
  END r0_rd_out[101]
  PIN r0_rd_out[102]
    DIRECTION OUTPUT ;
    USE SIGNAL ;
    SHAPE ABUTMENT ;
    PORT
      LAYER M3_m ;
      RECT 0 289.835 0.07 289.905 ;
    END
  END r0_rd_out[102]
  PIN r0_rd_out[103]
    DIRECTION OUTPUT ;
    USE SIGNAL ;
    SHAPE ABUTMENT ;
    PORT
      LAYER M3_m ;
      RECT 0 291.095 0.07 291.165 ;
    END
  END r0_rd_out[103]
  PIN r0_rd_out[104]
    DIRECTION OUTPUT ;
    USE SIGNAL ;
    SHAPE ABUTMENT ;
    PORT
      LAYER M3_m ;
      RECT 0 292.355 0.07 292.425 ;
    END
  END r0_rd_out[104]
  PIN r0_rd_out[105]
    DIRECTION OUTPUT ;
    USE SIGNAL ;
    SHAPE ABUTMENT ;
    PORT
      LAYER M3_m ;
      RECT 0 293.615 0.07 293.685 ;
    END
  END r0_rd_out[105]
  PIN r0_rd_out[106]
    DIRECTION OUTPUT ;
    USE SIGNAL ;
    SHAPE ABUTMENT ;
    PORT
      LAYER M3_m ;
      RECT 0 294.875 0.07 294.945 ;
    END
  END r0_rd_out[106]
  PIN r0_rd_out[107]
    DIRECTION OUTPUT ;
    USE SIGNAL ;
    SHAPE ABUTMENT ;
    PORT
      LAYER M3_m ;
      RECT 0 296.135 0.07 296.205 ;
    END
  END r0_rd_out[107]
  PIN r0_rd_out[108]
    DIRECTION OUTPUT ;
    USE SIGNAL ;
    SHAPE ABUTMENT ;
    PORT
      LAYER M3_m ;
      RECT 0 297.395 0.07 297.465 ;
    END
  END r0_rd_out[108]
  PIN r0_rd_out[109]
    DIRECTION OUTPUT ;
    USE SIGNAL ;
    SHAPE ABUTMENT ;
    PORT
      LAYER M3_m ;
      RECT 0 298.655 0.07 298.725 ;
    END
  END r0_rd_out[109]
  PIN r0_rd_out[110]
    DIRECTION OUTPUT ;
    USE SIGNAL ;
    SHAPE ABUTMENT ;
    PORT
      LAYER M3_m ;
      RECT 0 299.915 0.07 299.985 ;
    END
  END r0_rd_out[110]
  PIN r0_rd_out[111]
    DIRECTION OUTPUT ;
    USE SIGNAL ;
    SHAPE ABUTMENT ;
    PORT
      LAYER M3_m ;
      RECT 0 301.175 0.07 301.245 ;
    END
  END r0_rd_out[111]
  PIN r0_rd_out[112]
    DIRECTION OUTPUT ;
    USE SIGNAL ;
    SHAPE ABUTMENT ;
    PORT
      LAYER M3_m ;
      RECT 0 302.435 0.07 302.505 ;
    END
  END r0_rd_out[112]
  PIN r0_rd_out[113]
    DIRECTION OUTPUT ;
    USE SIGNAL ;
    SHAPE ABUTMENT ;
    PORT
      LAYER M3_m ;
      RECT 0 303.695 0.07 303.765 ;
    END
  END r0_rd_out[113]
  PIN r0_rd_out[114]
    DIRECTION OUTPUT ;
    USE SIGNAL ;
    SHAPE ABUTMENT ;
    PORT
      LAYER M3_m ;
      RECT 0 304.955 0.07 305.025 ;
    END
  END r0_rd_out[114]
  PIN r0_rd_out[115]
    DIRECTION OUTPUT ;
    USE SIGNAL ;
    SHAPE ABUTMENT ;
    PORT
      LAYER M3_m ;
      RECT 0 306.215 0.07 306.285 ;
    END
  END r0_rd_out[115]
  PIN r0_rd_out[116]
    DIRECTION OUTPUT ;
    USE SIGNAL ;
    SHAPE ABUTMENT ;
    PORT
      LAYER M3_m ;
      RECT 0 307.475 0.07 307.545 ;
    END
  END r0_rd_out[116]
  PIN r0_rd_out[117]
    DIRECTION OUTPUT ;
    USE SIGNAL ;
    SHAPE ABUTMENT ;
    PORT
      LAYER M3_m ;
      RECT 0 308.735 0.07 308.805 ;
    END
  END r0_rd_out[117]
  PIN r0_rd_out[118]
    DIRECTION OUTPUT ;
    USE SIGNAL ;
    SHAPE ABUTMENT ;
    PORT
      LAYER M3_m ;
      RECT 0 309.995 0.07 310.065 ;
    END
  END r0_rd_out[118]
  PIN r0_rd_out[119]
    DIRECTION OUTPUT ;
    USE SIGNAL ;
    SHAPE ABUTMENT ;
    PORT
      LAYER M3_m ;
      RECT 0 311.255 0.07 311.325 ;
    END
  END r0_rd_out[119]
  PIN r0_rd_out[120]
    DIRECTION OUTPUT ;
    USE SIGNAL ;
    SHAPE ABUTMENT ;
    PORT
      LAYER M3_m ;
      RECT 0 312.515 0.07 312.585 ;
    END
  END r0_rd_out[120]
  PIN r0_rd_out[121]
    DIRECTION OUTPUT ;
    USE SIGNAL ;
    SHAPE ABUTMENT ;
    PORT
      LAYER M3_m ;
      RECT 0 313.775 0.07 313.845 ;
    END
  END r0_rd_out[121]
  PIN r0_rd_out[122]
    DIRECTION OUTPUT ;
    USE SIGNAL ;
    SHAPE ABUTMENT ;
    PORT
      LAYER M3_m ;
      RECT 0 315.035 0.07 315.105 ;
    END
  END r0_rd_out[122]
  PIN r0_rd_out[123]
    DIRECTION OUTPUT ;
    USE SIGNAL ;
    SHAPE ABUTMENT ;
    PORT
      LAYER M3_m ;
      RECT 0 316.295 0.07 316.365 ;
    END
  END r0_rd_out[123]
  PIN r0_rd_out[124]
    DIRECTION OUTPUT ;
    USE SIGNAL ;
    SHAPE ABUTMENT ;
    PORT
      LAYER M3_m ;
      RECT 0 317.555 0.07 317.625 ;
    END
  END r0_rd_out[124]
  PIN r0_rd_out[125]
    DIRECTION OUTPUT ;
    USE SIGNAL ;
    SHAPE ABUTMENT ;
    PORT
      LAYER M3_m ;
      RECT 0 318.815 0.07 318.885 ;
    END
  END r0_rd_out[125]
  PIN r0_rd_out[126]
    DIRECTION OUTPUT ;
    USE SIGNAL ;
    SHAPE ABUTMENT ;
    PORT
      LAYER M3_m ;
      RECT 0 320.075 0.07 320.145 ;
    END
  END r0_rd_out[126]
  PIN r0_rd_out[127]
    DIRECTION OUTPUT ;
    USE SIGNAL ;
    SHAPE ABUTMENT ;
    PORT
      LAYER M3_m ;
      RECT 0 321.335 0.07 321.405 ;
    END
  END r0_rd_out[127]
  PIN w0_addr_in[0]
    DIRECTION INPUT ;
    USE SIGNAL ;
    SHAPE ABUTMENT ;
    PORT
      LAYER M3_m ;
      RECT 0 322.595 0.07 322.665 ;
    END
  END w0_addr_in[0]
  PIN w0_addr_in[1]
    DIRECTION INPUT ;
    USE SIGNAL ;
    SHAPE ABUTMENT ;
    PORT
      LAYER M3_m ;
      RECT 0 323.855 0.07 323.925 ;
    END
  END w0_addr_in[1]
  PIN w0_addr_in[2]
    DIRECTION INPUT ;
    USE SIGNAL ;
    SHAPE ABUTMENT ;
    PORT
      LAYER M3_m ;
      RECT 0 325.115 0.07 325.185 ;
    END
  END w0_addr_in[2]
  PIN w0_addr_in[3]
    DIRECTION INPUT ;
    USE SIGNAL ;
    SHAPE ABUTMENT ;
    PORT
      LAYER M3_m ;
      RECT 0 326.375 0.07 326.445 ;
    END
  END w0_addr_in[3]
  PIN w0_addr_in[4]
    DIRECTION INPUT ;
    USE SIGNAL ;
    SHAPE ABUTMENT ;
    PORT
      LAYER M3_m ;
      RECT 0 327.635 0.07 327.705 ;
    END
  END w0_addr_in[4]
  PIN w0_addr_in[5]
    DIRECTION INPUT ;
    USE SIGNAL ;
    SHAPE ABUTMENT ;
    PORT
      LAYER M3_m ;
      RECT 0 328.895 0.07 328.965 ;
    END
  END w0_addr_in[5]
  PIN w0_addr_in[6]
    DIRECTION INPUT ;
    USE SIGNAL ;
    SHAPE ABUTMENT ;
    PORT
      LAYER M3_m ;
      RECT 0 330.155 0.07 330.225 ;
    END
  END w0_addr_in[6]
  PIN w0_addr_in[7]
    DIRECTION INPUT ;
    USE SIGNAL ;
    SHAPE ABUTMENT ;
    PORT
      LAYER M3_m ;
      RECT 0 331.415 0.07 331.485 ;
    END
  END w0_addr_in[7]
  PIN w0_addr_in[8]
    DIRECTION INPUT ;
    USE SIGNAL ;
    SHAPE ABUTMENT ;
    PORT
      LAYER M3_m ;
      RECT 0 332.675 0.07 332.745 ;
    END
  END w0_addr_in[8]
  PIN r0_addr_in[0]
    DIRECTION INPUT ;
    USE SIGNAL ;
    SHAPE ABUTMENT ;
    PORT
      LAYER M3_m ;
      RECT 0 333.935 0.07 334.005 ;
    END
  END r0_addr_in[0]
  PIN r0_addr_in[1]
    DIRECTION INPUT ;
    USE SIGNAL ;
    SHAPE ABUTMENT ;
    PORT
      LAYER M3_m ;
      RECT 0 335.195 0.07 335.265 ;
    END
  END r0_addr_in[1]
  PIN r0_addr_in[2]
    DIRECTION INPUT ;
    USE SIGNAL ;
    SHAPE ABUTMENT ;
    PORT
      LAYER M3_m ;
      RECT 0 336.455 0.07 336.525 ;
    END
  END r0_addr_in[2]
  PIN r0_addr_in[3]
    DIRECTION INPUT ;
    USE SIGNAL ;
    SHAPE ABUTMENT ;
    PORT
      LAYER M3_m ;
      RECT 0 337.715 0.07 337.785 ;
    END
  END r0_addr_in[3]
  PIN r0_addr_in[4]
    DIRECTION INPUT ;
    USE SIGNAL ;
    SHAPE ABUTMENT ;
    PORT
      LAYER M3_m ;
      RECT 0 338.975 0.07 339.045 ;
    END
  END r0_addr_in[4]
  PIN r0_addr_in[5]
    DIRECTION INPUT ;
    USE SIGNAL ;
    SHAPE ABUTMENT ;
    PORT
      LAYER M3_m ;
      RECT 0 340.235 0.07 340.305 ;
    END
  END r0_addr_in[5]
  PIN r0_addr_in[6]
    DIRECTION INPUT ;
    USE SIGNAL ;
    SHAPE ABUTMENT ;
    PORT
      LAYER M3_m ;
      RECT 0 341.495 0.07 341.565 ;
    END
  END r0_addr_in[6]
  PIN r0_addr_in[7]
    DIRECTION INPUT ;
    USE SIGNAL ;
    SHAPE ABUTMENT ;
    PORT
      LAYER M3_m ;
      RECT 0 342.755 0.07 342.825 ;
    END
  END r0_addr_in[7]
  PIN r0_addr_in[8]
    DIRECTION INPUT ;
    USE SIGNAL ;
    SHAPE ABUTMENT ;
    PORT
      LAYER M3_m ;
      RECT 0 344.015 0.07 344.085 ;
    END
  END r0_addr_in[8]
  PIN w0_we_in
    DIRECTION INPUT ;
    USE SIGNAL ;
    SHAPE ABUTMENT ;
    PORT
      LAYER M3_m ;
      RECT 0 345.275 0.07 345.345 ;
    END
  END w0_we_in
  PIN w0_ce_in
    DIRECTION INPUT ;
    USE SIGNAL ;
    SHAPE ABUTMENT ;
    PORT
      LAYER M3_m ;
      RECT 0 346.535 0.07 346.605 ;
    END
  END w0_ce_in
  PIN w0_clk
    DIRECTION INPUT ;
    USE SIGNAL ;
    SHAPE ABUTMENT ;
    PORT
      LAYER M3_m ;
      RECT 0 347.795 0.07 347.865 ;
    END
  END w0_clk
  PIN r0_ce_in
    DIRECTION INPUT ;
    USE SIGNAL ;
    SHAPE ABUTMENT ;
    PORT
      LAYER M3_m ;
      RECT 0 349.055 0.07 349.125 ;
    END
  END r0_ce_in
  PIN r0_clk
    DIRECTION INPUT ;
    USE SIGNAL ;
    SHAPE ABUTMENT ;
    PORT
      LAYER M3_m ;
      RECT 0 350.315 0.07 350.385 ;
    END
  END r0_clk
  PIN VSS
    DIRECTION INOUT ;
    USE GROUND ;
    PORT
      LAYER M4_m ;
      RECT 1 0.84 1.28 353.36 ;
      RECT 3.24 0.84 3.52 353.36 ;
      RECT 5.48 0.84 5.76 353.36 ;
      RECT 7.72 0.84 8 353.36 ;
      RECT 9.96 0.84 10.24 353.36 ;
      RECT 12.2 0.84 12.48 353.36 ;
      RECT 14.44 0.84 14.72 353.36 ;
      RECT 16.68 0.84 16.96 353.36 ;
      RECT 18.92 0.84 19.2 353.36 ;
      RECT 21.16 0.84 21.44 353.36 ;
      RECT 23.4 0.84 23.68 353.36 ;
      RECT 25.64 0.84 25.92 353.36 ;
      RECT 27.88 0.84 28.16 353.36 ;
      RECT 30.12 0.84 30.4 353.36 ;
      RECT 32.36 0.84 32.64 353.36 ;
      RECT 34.6 0.84 34.88 353.36 ;
      RECT 36.84 0.84 37.12 353.36 ;
      RECT 39.08 0.84 39.36 353.36 ;
      RECT 41.32 0.84 41.6 353.36 ;
      RECT 43.56 0.84 43.84 353.36 ;
      RECT 45.8 0.84 46.08 353.36 ;
      RECT 48.04 0.84 48.32 353.36 ;
      RECT 50.28 0.84 50.56 353.36 ;
      RECT 52.52 0.84 52.8 353.36 ;
      RECT 54.76 0.84 55.04 353.36 ;
      RECT 57 0.84 57.28 353.36 ;
      RECT 59.24 0.84 59.52 353.36 ;
      RECT 61.48 0.84 61.76 353.36 ;
      RECT 63.72 0.84 64 353.36 ;
      RECT 65.96 0.84 66.24 353.36 ;
      RECT 68.2 0.84 68.48 353.36 ;
      RECT 70.44 0.84 70.72 353.36 ;
      RECT 72.68 0.84 72.96 353.36 ;
      RECT 74.92 0.84 75.2 353.36 ;
      RECT 77.16 0.84 77.44 353.36 ;
      RECT 79.4 0.84 79.68 353.36 ;
      RECT 81.64 0.84 81.92 353.36 ;
      RECT 83.88 0.84 84.16 353.36 ;
      RECT 86.12 0.84 86.4 353.36 ;
      RECT 88.36 0.84 88.64 353.36 ;
      RECT 90.6 0.84 90.88 353.36 ;
      RECT 92.84 0.84 93.12 353.36 ;
      RECT 95.08 0.84 95.36 353.36 ;
      RECT 97.32 0.84 97.6 353.36 ;
      RECT 99.56 0.84 99.84 353.36 ;
      RECT 101.8 0.84 102.08 353.36 ;
      RECT 104.04 0.84 104.32 353.36 ;
      RECT 106.28 0.84 106.56 353.36 ;
      RECT 108.52 0.84 108.8 353.36 ;
      RECT 110.76 0.84 111.04 353.36 ;
      RECT 113 0.84 113.28 353.36 ;
      RECT 115.24 0.84 115.52 353.36 ;
      RECT 117.48 0.84 117.76 353.36 ;
      RECT 119.72 0.84 120 353.36 ;
      RECT 121.96 0.84 122.24 353.36 ;
      RECT 124.2 0.84 124.48 353.36 ;
      RECT 126.44 0.84 126.72 353.36 ;
      RECT 128.68 0.84 128.96 353.36 ;
      RECT 130.92 0.84 131.2 353.36 ;
      RECT 133.16 0.84 133.44 353.36 ;
      RECT 135.4 0.84 135.68 353.36 ;
      RECT 137.64 0.84 137.92 353.36 ;
      RECT 139.88 0.84 140.16 353.36 ;
      RECT 142.12 0.84 142.4 353.36 ;
      RECT 144.36 0.84 144.64 353.36 ;
      RECT 146.6 0.84 146.88 353.36 ;
      RECT 148.84 0.84 149.12 353.36 ;
      RECT 151.08 0.84 151.36 353.36 ;
      RECT 153.32 0.84 153.6 353.36 ;
      RECT 155.56 0.84 155.84 353.36 ;
      RECT 157.8 0.84 158.08 353.36 ;
      RECT 160.04 0.84 160.32 353.36 ;
      RECT 162.28 0.84 162.56 353.36 ;
      RECT 164.52 0.84 164.8 353.36 ;
      RECT 166.76 0.84 167.04 353.36 ;
      RECT 169 0.84 169.28 353.36 ;
      RECT 171.24 0.84 171.52 353.36 ;
      RECT 173.48 0.84 173.76 353.36 ;
      RECT 175.72 0.84 176 353.36 ;
      RECT 177.96 0.84 178.24 353.36 ;
      RECT 180.2 0.84 180.48 353.36 ;
      RECT 182.44 0.84 182.72 353.36 ;
      RECT 184.68 0.84 184.96 353.36 ;
      RECT 186.92 0.84 187.2 353.36 ;
      RECT 189.16 0.84 189.44 353.36 ;
      RECT 191.4 0.84 191.68 353.36 ;
      RECT 193.64 0.84 193.92 353.36 ;
      RECT 195.88 0.84 196.16 353.36 ;
      RECT 198.12 0.84 198.4 353.36 ;
      RECT 200.36 0.84 200.64 353.36 ;
      RECT 202.6 0.84 202.88 353.36 ;
      RECT 204.84 0.84 205.12 353.36 ;
      RECT 207.08 0.84 207.36 353.36 ;
      RECT 209.32 0.84 209.6 353.36 ;
      RECT 211.56 0.84 211.84 353.36 ;
      RECT 213.8 0.84 214.08 353.36 ;
      RECT 216.04 0.84 216.32 353.36 ;
      RECT 218.28 0.84 218.56 353.36 ;
      RECT 220.52 0.84 220.8 353.36 ;
      RECT 222.76 0.84 223.04 353.36 ;
      RECT 225 0.84 225.28 353.36 ;
      RECT 227.24 0.84 227.52 353.36 ;
      RECT 229.48 0.84 229.76 353.36 ;
      RECT 231.72 0.84 232 353.36 ;
      RECT 233.96 0.84 234.24 353.36 ;
      RECT 236.2 0.84 236.48 353.36 ;
      RECT 238.44 0.84 238.72 353.36 ;
      RECT 240.68 0.84 240.96 353.36 ;
      RECT 242.92 0.84 243.2 353.36 ;
      RECT 245.16 0.84 245.44 353.36 ;
      RECT 247.4 0.84 247.68 353.36 ;
      RECT 249.64 0.84 249.92 353.36 ;
      RECT 251.88 0.84 252.16 353.36 ;
      RECT 254.12 0.84 254.4 353.36 ;
      RECT 256.36 0.84 256.64 353.36 ;
      RECT 258.6 0.84 258.88 353.36 ;
      RECT 260.84 0.84 261.12 353.36 ;
      RECT 263.08 0.84 263.36 353.36 ;
      RECT 265.32 0.84 265.6 353.36 ;
      RECT 267.56 0.84 267.84 353.36 ;
      RECT 269.8 0.84 270.08 353.36 ;
      RECT 272.04 0.84 272.32 353.36 ;
      RECT 274.28 0.84 274.56 353.36 ;
      RECT 276.52 0.84 276.8 353.36 ;
      RECT 278.76 0.84 279.04 353.36 ;
      RECT 281 0.84 281.28 353.36 ;
      RECT 283.24 0.84 283.52 353.36 ;
      RECT 285.48 0.84 285.76 353.36 ;
      RECT 287.72 0.84 288 353.36 ;
      RECT 289.96 0.84 290.24 353.36 ;
      RECT 292.2 0.84 292.48 353.36 ;
    END
  END VSS
  PIN VDD
    DIRECTION INOUT ;
    USE POWER ;
    PORT
      LAYER M4_m ;
      RECT 2.12 0.84 2.4 353.36 ;
      RECT 4.36 0.84 4.64 353.36 ;
      RECT 6.6 0.84 6.88 353.36 ;
      RECT 8.84 0.84 9.12 353.36 ;
      RECT 11.08 0.84 11.36 353.36 ;
      RECT 13.32 0.84 13.6 353.36 ;
      RECT 15.56 0.84 15.84 353.36 ;
      RECT 17.8 0.84 18.08 353.36 ;
      RECT 20.04 0.84 20.32 353.36 ;
      RECT 22.28 0.84 22.56 353.36 ;
      RECT 24.52 0.84 24.8 353.36 ;
      RECT 26.76 0.84 27.04 353.36 ;
      RECT 29 0.84 29.28 353.36 ;
      RECT 31.24 0.84 31.52 353.36 ;
      RECT 33.48 0.84 33.76 353.36 ;
      RECT 35.72 0.84 36 353.36 ;
      RECT 37.96 0.84 38.24 353.36 ;
      RECT 40.2 0.84 40.48 353.36 ;
      RECT 42.44 0.84 42.72 353.36 ;
      RECT 44.68 0.84 44.96 353.36 ;
      RECT 46.92 0.84 47.2 353.36 ;
      RECT 49.16 0.84 49.44 353.36 ;
      RECT 51.4 0.84 51.68 353.36 ;
      RECT 53.64 0.84 53.92 353.36 ;
      RECT 55.88 0.84 56.16 353.36 ;
      RECT 58.12 0.84 58.4 353.36 ;
      RECT 60.36 0.84 60.64 353.36 ;
      RECT 62.6 0.84 62.88 353.36 ;
      RECT 64.84 0.84 65.12 353.36 ;
      RECT 67.08 0.84 67.36 353.36 ;
      RECT 69.32 0.84 69.6 353.36 ;
      RECT 71.56 0.84 71.84 353.36 ;
      RECT 73.8 0.84 74.08 353.36 ;
      RECT 76.04 0.84 76.32 353.36 ;
      RECT 78.28 0.84 78.56 353.36 ;
      RECT 80.52 0.84 80.8 353.36 ;
      RECT 82.76 0.84 83.04 353.36 ;
      RECT 85 0.84 85.28 353.36 ;
      RECT 87.24 0.84 87.52 353.36 ;
      RECT 89.48 0.84 89.76 353.36 ;
      RECT 91.72 0.84 92 353.36 ;
      RECT 93.96 0.84 94.24 353.36 ;
      RECT 96.2 0.84 96.48 353.36 ;
      RECT 98.44 0.84 98.72 353.36 ;
      RECT 100.68 0.84 100.96 353.36 ;
      RECT 102.92 0.84 103.2 353.36 ;
      RECT 105.16 0.84 105.44 353.36 ;
      RECT 107.4 0.84 107.68 353.36 ;
      RECT 109.64 0.84 109.92 353.36 ;
      RECT 111.88 0.84 112.16 353.36 ;
      RECT 114.12 0.84 114.4 353.36 ;
      RECT 116.36 0.84 116.64 353.36 ;
      RECT 118.6 0.84 118.88 353.36 ;
      RECT 120.84 0.84 121.12 353.36 ;
      RECT 123.08 0.84 123.36 353.36 ;
      RECT 125.32 0.84 125.6 353.36 ;
      RECT 127.56 0.84 127.84 353.36 ;
      RECT 129.8 0.84 130.08 353.36 ;
      RECT 132.04 0.84 132.32 353.36 ;
      RECT 134.28 0.84 134.56 353.36 ;
      RECT 136.52 0.84 136.8 353.36 ;
      RECT 138.76 0.84 139.04 353.36 ;
      RECT 141 0.84 141.28 353.36 ;
      RECT 143.24 0.84 143.52 353.36 ;
      RECT 145.48 0.84 145.76 353.36 ;
      RECT 147.72 0.84 148 353.36 ;
      RECT 149.96 0.84 150.24 353.36 ;
      RECT 152.2 0.84 152.48 353.36 ;
      RECT 154.44 0.84 154.72 353.36 ;
      RECT 156.68 0.84 156.96 353.36 ;
      RECT 158.92 0.84 159.2 353.36 ;
      RECT 161.16 0.84 161.44 353.36 ;
      RECT 163.4 0.84 163.68 353.36 ;
      RECT 165.64 0.84 165.92 353.36 ;
      RECT 167.88 0.84 168.16 353.36 ;
      RECT 170.12 0.84 170.4 353.36 ;
      RECT 172.36 0.84 172.64 353.36 ;
      RECT 174.6 0.84 174.88 353.36 ;
      RECT 176.84 0.84 177.12 353.36 ;
      RECT 179.08 0.84 179.36 353.36 ;
      RECT 181.32 0.84 181.6 353.36 ;
      RECT 183.56 0.84 183.84 353.36 ;
      RECT 185.8 0.84 186.08 353.36 ;
      RECT 188.04 0.84 188.32 353.36 ;
      RECT 190.28 0.84 190.56 353.36 ;
      RECT 192.52 0.84 192.8 353.36 ;
      RECT 194.76 0.84 195.04 353.36 ;
      RECT 197 0.84 197.28 353.36 ;
      RECT 199.24 0.84 199.52 353.36 ;
      RECT 201.48 0.84 201.76 353.36 ;
      RECT 203.72 0.84 204 353.36 ;
      RECT 205.96 0.84 206.24 353.36 ;
      RECT 208.2 0.84 208.48 353.36 ;
      RECT 210.44 0.84 210.72 353.36 ;
      RECT 212.68 0.84 212.96 353.36 ;
      RECT 214.92 0.84 215.2 353.36 ;
      RECT 217.16 0.84 217.44 353.36 ;
      RECT 219.4 0.84 219.68 353.36 ;
      RECT 221.64 0.84 221.92 353.36 ;
      RECT 223.88 0.84 224.16 353.36 ;
      RECT 226.12 0.84 226.4 353.36 ;
      RECT 228.36 0.84 228.64 353.36 ;
      RECT 230.6 0.84 230.88 353.36 ;
      RECT 232.84 0.84 233.12 353.36 ;
      RECT 235.08 0.84 235.36 353.36 ;
      RECT 237.32 0.84 237.6 353.36 ;
      RECT 239.56 0.84 239.84 353.36 ;
      RECT 241.8 0.84 242.08 353.36 ;
      RECT 244.04 0.84 244.32 353.36 ;
      RECT 246.28 0.84 246.56 353.36 ;
      RECT 248.52 0.84 248.8 353.36 ;
      RECT 250.76 0.84 251.04 353.36 ;
      RECT 253 0.84 253.28 353.36 ;
      RECT 255.24 0.84 255.52 353.36 ;
      RECT 257.48 0.84 257.76 353.36 ;
      RECT 259.72 0.84 260 353.36 ;
      RECT 261.96 0.84 262.24 353.36 ;
      RECT 264.2 0.84 264.48 353.36 ;
      RECT 266.44 0.84 266.72 353.36 ;
      RECT 268.68 0.84 268.96 353.36 ;
      RECT 270.92 0.84 271.2 353.36 ;
      RECT 273.16 0.84 273.44 353.36 ;
      RECT 275.4 0.84 275.68 353.36 ;
      RECT 277.64 0.84 277.92 353.36 ;
      RECT 279.88 0.84 280.16 353.36 ;
      RECT 282.12 0.84 282.4 353.36 ;
      RECT 284.36 0.84 284.64 353.36 ;
      RECT 286.6 0.84 286.88 353.36 ;
      RECT 288.84 0.84 289.12 353.36 ;
      RECT 291.08 0.84 291.36 353.36 ;
      RECT 293.32 0.84 293.6 353.36 ;
    END
  END VDD
  OBS
    LAYER M1_m ;
    RECT 0 0 294.12 354.2 ;
    LAYER M2_m ;
    RECT 0 0 294.12 354.2 ;
  END
END ht45_leon3vtabus_mem_0_ext_upper

END LIBRARY
